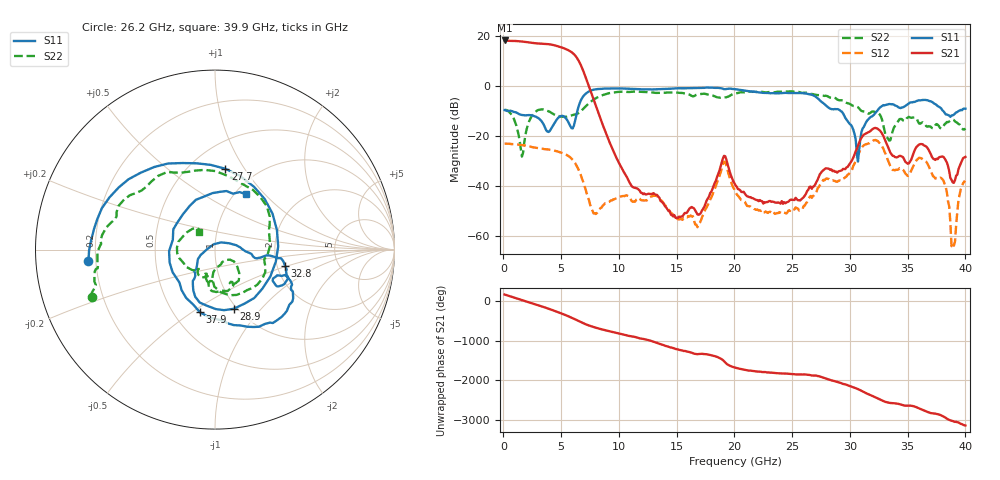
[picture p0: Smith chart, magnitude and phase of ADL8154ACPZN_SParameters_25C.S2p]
! Analog Devices, Inc."
! Device:	ADL8154ACPZN
! Description:	"10 MHz to 6 GHz, Wideband, Low Noise Amplifier"
! Conditions:	Vdd = 5.0 V
!		IDQ = 125 mA
!		Pin = -25 dBm
!		Operating Temperature = +25 C (at package bottom)
! Product validation unit SN30 soldered down to Evaluation Board as shown on ADL8154-EVALZ User Guide. Board loss de-embedded from S21 magnitude.  All other RF measurements reference to RF coaxial connector.
! Frequency (GHz)	S11_Mag (dB)	S11_Phase (deg)	S21_Mag (dB)	S21_Phase (deg)	S12_Mag (dB)	S12_Phase (deg)	S22_Mag (dB)	S22_Phase (deg)
#  GHZ  S  DB  R 50
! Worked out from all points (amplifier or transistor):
!   400 points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, 110 MHz to 40 GHz, reference 50 ohm
!   highest |S21| = 18.3 dB at 110 MHz (marker M1)
!   |S21| within 3 dB of that: start of sweep to 5.166 GHz
!   unconditionally stable (mu >= 1): start of sweep to end of sweep
!   at 6.708 GHz: K = 7.50, MAG = 10.3 dB, |S12| = -35.7 dB
!   at 20.11 GHz: K = 842.37, MAG = -30.9 dB, |S12| = -42.6 dB
!   at 40 GHz: K = 955.25, MAG = -27.7 dB, |S12| = -38.6 dB
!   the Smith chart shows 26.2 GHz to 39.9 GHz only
!   S11 on the Smith chart (normalised r, x): 26.2 GHz: 0.17, -0.04; 27.7 GHz: 0.73, +0.83; 28.9 GHz: 0.96, -0.72; 32.8 GHz: 2.21, -0.47; 37.9 GHz: 0.67, -0.54; 39.9 GHz: 1.12, +0.79
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0.11  -9.65 -179.1  18.27 170.5  -23.07 -5.9  -9.47 168.8
1.01  -10.44 139.5  18.07 87.2  -23.29 -73.5  -14.29 86.8
1.91  -11.73 109.6  17.66 3.5  -23.86 -142.1  -19.60 -132.8
2.809  -12.25 60.9  17.12 -79.6  -24.74 148.7  -10.23 145.4
3.709  -17.67 -46.3  16.84 -166.6  -25.30 76.9  -9.78 82.7
4.109  -17.34 -134.9  16.65 152.1  -25.57 43.4  -10.56 56.3
4.609  -13.52 146.8  16.10 98.7  -26.08 0.0  -11.75 19.3
5.409  -12.89 56.6  14.82 8.3  -27.40 -74.2  -12.32 -62.5
6.108  -15.85 -101.8  12.79 -81.7  -30.16 -149.3  -11.49 -138.2
6.808  -4.89 133.2  7.34 180.2  -37.10 125.8  -9.64 166.3
7.908  -1.38 42.7  -6.66 60.8  -50.92 -27.7  -5.15 77.8
13.407  -1.27 176.7  -44.23 17.0  -44.59 14.0  -2.74 173.6
20.105  -1.30 15.8  -39.81 120.6  -42.56 118.6  -2.97 -2.5
26.203  -3.00 -175.0  -43.09 -52.7  -46.99 -55.8  -2.67 -159.0
26.803  -3.66 153.7  -40.33 -76.6  -44.03 -78.9  -3.26 -167.9
27.703  -6.86 82.7  -33.74 -129.0  -37.59 -135.8  -3.87 178.1
28.903  -9.22 -72.6  -34.69 121.4  -38.31 120.5  -5.38 143.9
32.802  -7.96 -12.9  -19.18 10.8  -24.32 8.6  -13.71 -91.0
33.402  -7.18 -21.9  -25.53 -45.7  -31.02 -45.9  -21.86 -61.1
37.901  -8.90 -103.6  -28.33 -2.5  -36.84 0.7  -17.06 -129.9
39.9  -9.04 61.0  -28.61 107.3  -38.20 87.4  -17.45 131.9
40  -9.08 57.2  -28.38 101.8  -38.56 78.7  -16.98 132.4
